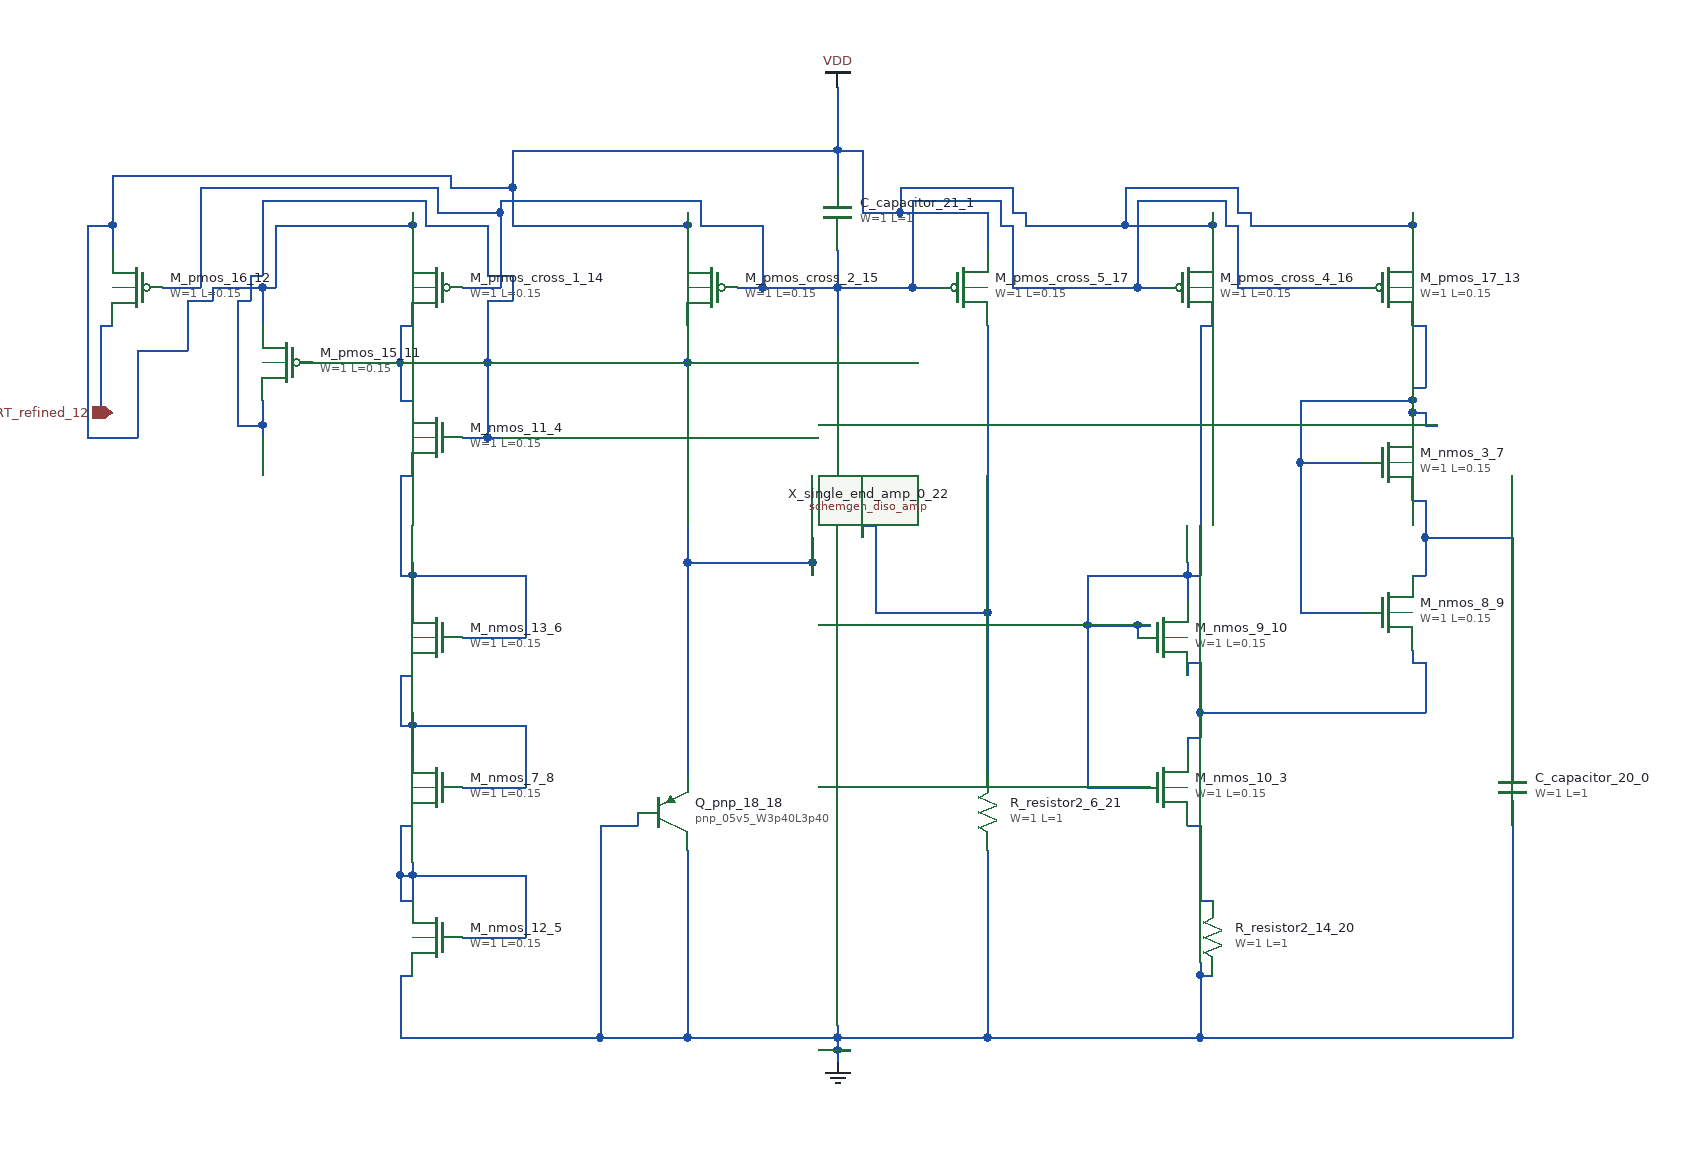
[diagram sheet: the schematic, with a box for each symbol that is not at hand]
v {xschem version=3.4.8 file_version=1.2}
G {}
K {}
V {}
S {}
E {}
C {sky130_fd_pr/cap_mim_m3_1.sym} 1180 600 0 0 {name="C_capacitor_20_0" model=cap_mim_m3_1 W=1 L=1 MF=1 spiceprefix=X}
C {sky130_fd_pr/cap_mim_m3_1.sym} 640 140 2 0 {name="C_capacitor_21_1" model=cap_mim_m3_1 W=1 L=1 MF=1 spiceprefix=X}
C {devices/gnd.sym} 640 820 0 0 {name="l_gnd_19_2" lab="GND"}
C {sky130_fd_pr/nfet3_01v8.sym} 900 600 2 1 {name="M_nmos_10_3"
W=1
L=0.15
body=GND
nf=1
mult=1
ad="expr('int((@nf + 1)/2) * @W / @nf * 0.29')"
pd="expr('2*int((@nf + 1)/2) * (@W / @nf + 0.29)')"
as="expr('int((@nf + 2)/2) * @W / @nf * 0.29')"
ps="expr('2*int((@nf + 2)/2) * (@W / @nf + 0.29)')"
nrd="expr('0.29 / @W ')" nrs="expr('0.29 / @W ')"
sa=0 sb=0 sd=0
model=nfet_01v8
spiceprefix=X
}
C {sky130_fd_pr/nfet3_01v8.sym} 320 320 0 1 {name="M_nmos_11_4"
W=1
L=0.15
body=GND
nf=1
mult=1
ad="expr('int((@nf + 1)/2) * @W / @nf * 0.29')"
pd="expr('2*int((@nf + 1)/2) * (@W / @nf + 0.29)')"
as="expr('int((@nf + 2)/2) * @W / @nf * 0.29')"
ps="expr('2*int((@nf + 2)/2) * (@W / @nf + 0.29)')"
nrd="expr('0.29 / @W ')" nrs="expr('0.29 / @W ')"
sa=0 sb=0 sd=0
model=nfet_01v8
spiceprefix=X
}
C {sky130_fd_pr/nfet3_01v8.sym} 320 720 0 1 {name="M_nmos_12_5"
W=1
L=0.15
body=GND
nf=1
mult=1
ad="expr('int((@nf + 1)/2) * @W / @nf * 0.29')"
pd="expr('2*int((@nf + 1)/2) * (@W / @nf + 0.29)')"
as="expr('int((@nf + 2)/2) * @W / @nf * 0.29')"
ps="expr('2*int((@nf + 2)/2) * (@W / @nf + 0.29)')"
nrd="expr('0.29 / @W ')" nrs="expr('0.29 / @W ')"
sa=0 sb=0 sd=0
model=nfet_01v8
spiceprefix=X
}
C {sky130_fd_pr/nfet3_01v8.sym} 320 480 0 1 {name="M_nmos_13_6"
W=1
L=0.15
body=GND
nf=1
mult=1
ad="expr('int((@nf + 1)/2) * @W / @nf * 0.29')"
pd="expr('2*int((@nf + 1)/2) * (@W / @nf + 0.29)')"
as="expr('int((@nf + 2)/2) * @W / @nf * 0.29')"
ps="expr('2*int((@nf + 2)/2) * (@W / @nf + 0.29)')"
nrd="expr('0.29 / @W ')" nrs="expr('0.29 / @W ')"
sa=0 sb=0 sd=0
model=nfet_01v8
spiceprefix=X
}
C {sky130_fd_pr/nfet3_01v8.sym} 1080 340 0 0 {name="M_nmos_3_7"
W=1
L=0.15
body=GND
nf=1
mult=1
ad="expr('int((@nf + 1)/2) * @W / @nf * 0.29')"
pd="expr('2*int((@nf + 1)/2) * (@W / @nf + 0.29)')"
as="expr('int((@nf + 2)/2) * @W / @nf * 0.29')"
ps="expr('2*int((@nf + 2)/2) * (@W / @nf + 0.29)')"
nrd="expr('0.29 / @W ')" nrs="expr('0.29 / @W ')"
sa=0 sb=0 sd=0
model=nfet_01v8
spiceprefix=X
}
C {sky130_fd_pr/nfet3_01v8.sym} 320 600 0 1 {name="M_nmos_7_8"
W=1
L=0.15
body=GND
nf=1
mult=1
ad="expr('int((@nf + 1)/2) * @W / @nf * 0.29')"
pd="expr('2*int((@nf + 1)/2) * (@W / @nf + 0.29)')"
as="expr('int((@nf + 2)/2) * @W / @nf * 0.29')"
ps="expr('2*int((@nf + 2)/2) * (@W / @nf + 0.29)')"
nrd="expr('0.29 / @W ')" nrs="expr('0.29 / @W ')"
sa=0 sb=0 sd=0
model=nfet_01v8
spiceprefix=X
}
C {sky130_fd_pr/nfet3_01v8.sym} 1080 460 2 1 {name="M_nmos_8_9"
W=1
L=0.15
body=GND
nf=1
mult=1
ad="expr('int((@nf + 1)/2) * @W / @nf * 0.29')"
pd="expr('2*int((@nf + 1)/2) * (@W / @nf + 0.29)')"
as="expr('int((@nf + 2)/2) * @W / @nf * 0.29')"
ps="expr('2*int((@nf + 2)/2) * (@W / @nf + 0.29)')"
nrd="expr('0.29 / @W ')" nrs="expr('0.29 / @W ')"
sa=0 sb=0 sd=0
model=nfet_01v8
spiceprefix=X
}
C {sky130_fd_pr/nfet3_01v8.sym} 900 480 0 0 {name="M_nmos_9_10"
W=1
L=0.15
body=GND
nf=1
mult=1
ad="expr('int((@nf + 1)/2) * @W / @nf * 0.29')"
pd="expr('2*int((@nf + 1)/2) * (@W / @nf + 0.29)')"
as="expr('int((@nf + 2)/2) * @W / @nf * 0.29')"
ps="expr('2*int((@nf + 2)/2) * (@W / @nf + 0.29)')"
nrd="expr('0.29 / @W ')" nrs="expr('0.29 / @W ')"
sa=0 sb=0 sd=0
model=nfet_01v8
spiceprefix=X
}
C {sky130_fd_pr/pfet3_01v8.sym} 200 260 0 1 {name="M_pmos_15_11"
W=1
L=0.15
body=VDD
nf=1
mult=1
ad="expr('int((@nf + 1)/2) * @W / @nf * 0.29')"
pd="expr('2*int((@nf + 1)/2) * (@W / @nf + 0.29)')"
as="expr('int((@nf + 2)/2) * @W / @nf * 0.29')"
ps="expr('2*int((@nf + 2)/2) * (@W / @nf + 0.29)')"
nrd="expr('0.29 / @W ')" nrs="expr('0.29 / @W ')"
sa=0 sb=0 sd=0
model=pfet_01v8
spiceprefix=X
}
C {sky130_fd_pr/pfet3_01v8.sym} 80 200 0 1 {name="M_pmos_16_12"
W=1
L=0.15
body=VDD
nf=1
mult=1
ad="expr('int((@nf + 1)/2) * @W / @nf * 0.29')"
pd="expr('2*int((@nf + 1)/2) * (@W / @nf + 0.29)')"
as="expr('int((@nf + 2)/2) * @W / @nf * 0.29')"
ps="expr('2*int((@nf + 2)/2) * (@W / @nf + 0.29)')"
nrd="expr('0.29 / @W ')" nrs="expr('0.29 / @W ')"
sa=0 sb=0 sd=0
model=pfet_01v8
spiceprefix=X
}
C {sky130_fd_pr/pfet3_01v8.sym} 1080 200 0 0 {name="M_pmos_17_13"
W=1
L=0.15
body=VDD
nf=1
mult=1
ad="expr('int((@nf + 1)/2) * @W / @nf * 0.29')"
pd="expr('2*int((@nf + 1)/2) * (@W / @nf + 0.29)')"
as="expr('int((@nf + 2)/2) * @W / @nf * 0.29')"
ps="expr('2*int((@nf + 2)/2) * (@W / @nf + 0.29)')"
nrd="expr('0.29 / @W ')" nrs="expr('0.29 / @W ')"
sa=0 sb=0 sd=0
model=pfet_01v8
spiceprefix=X
}
C {sky130_fd_pr/pfet3_01v8.sym} 320 200 0 1 {name="M_pmos_cross_1_14"
W=1
L=0.15
body=VDD
nf=1
mult=1
ad="expr('int((@nf + 1)/2) * @W / @nf * 0.29')"
pd="expr('2*int((@nf + 1)/2) * (@W / @nf + 0.29)')"
as="expr('int((@nf + 2)/2) * @W / @nf * 0.29')"
ps="expr('2*int((@nf + 2)/2) * (@W / @nf + 0.29)')"
nrd="expr('0.29 / @W ')" nrs="expr('0.29 / @W ')"
sa=0 sb=0 sd=0
model=pfet_01v8
spiceprefix=X
}
C {sky130_fd_pr/pfet3_01v8.sym} 540 200 0 1 {name="M_pmos_cross_2_15"
W=1
L=0.15
body=VDD
nf=1
mult=1
ad="expr('int((@nf + 1)/2) * @W / @nf * 0.29')"
pd="expr('2*int((@nf + 1)/2) * (@W / @nf + 0.29)')"
as="expr('int((@nf + 2)/2) * @W / @nf * 0.29')"
ps="expr('2*int((@nf + 2)/2) * (@W / @nf + 0.29)')"
nrd="expr('0.29 / @W ')" nrs="expr('0.29 / @W ')"
sa=0 sb=0 sd=0
model=pfet_01v8
spiceprefix=X
}
C {sky130_fd_pr/pfet3_01v8.sym} 920 200 0 0 {name="M_pmos_cross_4_16"
W=1
L=0.15
body=VDD
nf=1
mult=1
ad="expr('int((@nf + 1)/2) * @W / @nf * 0.29')"
pd="expr('2*int((@nf + 1)/2) * (@W / @nf + 0.29)')"
as="expr('int((@nf + 2)/2) * @W / @nf * 0.29')"
ps="expr('2*int((@nf + 2)/2) * (@W / @nf + 0.29)')"
nrd="expr('0.29 / @W ')" nrs="expr('0.29 / @W ')"
sa=0 sb=0 sd=0
model=pfet_01v8
spiceprefix=X
}
C {sky130_fd_pr/pfet3_01v8.sym} 740 200 0 0 {name="M_pmos_cross_5_17"
W=1
L=0.15
body=VDD
nf=1
mult=1
ad="expr('int((@nf + 1)/2) * @W / @nf * 0.29')"
pd="expr('2*int((@nf + 1)/2) * (@W / @nf + 0.29)')"
as="expr('int((@nf + 2)/2) * @W / @nf * 0.29')"
ps="expr('2*int((@nf + 2)/2) * (@W / @nf + 0.29)')"
nrd="expr('0.29 / @W ')" nrs="expr('0.29 / @W ')"
sa=0 sb=0 sd=0
model=pfet_01v8
spiceprefix=X
}
C {sky130_fd_pr/pnp_05v5.sym} 500 620 0 0 {name="Q_pnp_18_18"
model=pnp_05v5_W3p40L3p40
m=1
spiceprefix=X
}
C {devices/ipin.sym} 60 300 0 0 {name="p_port_27_19" lab="PORT_refined_12"}
C {sky130_fd_pr/res_generic_po.sym} 940 720 2 0 {name="R_resistor2_14_20"
W=1
L=1
model=res_generic_po
spiceprefix=X
mult=1}
C {sky130_fd_pr/res_generic_po.sym} 760 620 2 0 {name="R_resistor2_6_21"
W=1
L=1
model=res_generic_po
spiceprefix=X
mult=1}
C {schemgen_diso_amp.sym} 640 320 1 1 {name="X_single_end_amp_0_22"}
C {devices/vdd.sym} 640 40 0 0 {name="l_vdd_22_23" lab="VDD"}
N 640 810 650 810 {}
N 290 800 450 800 {}
N 450 800 520 800 {}
N 520 800 640 800 {}
N 640 800 760 800 {}
N 760 800 930 800 {}
N 930 800 1180 800 {}
N 290 750 300 750 {}
N 930 750 940 750 {}
N 450 630 480 630 {}
N 290 800 290 750 {}
N 450 800 450 630 {}
N 480 630 480 620 {}
N 520 800 520 650 {}
N 640 820 640 810 {}
N 640 810 640 800 {}
N 640 800 640 790 {}
N 760 800 760 650 {}
N 930 800 930 750 {}
N 930 750 930 740 {}
N 1180 800 1180 630 {}
N 1180 630 1180 610 {}
N 1100 430 1110 430 {}
N 1110 400 1180 400 {}
N 1100 370 1110 370 {}
N 1110 430 1110 400 {}
N 1110 400 1110 370 {}
N 1180 590 1180 570 {}
N 1180 570 1180 400 {}
N 520 420 620 420 {}
N 340 320 360 320 {}
N 360 320 370 320 {}
N 160 310 180 310 {}
N 360 260 520 260 {}
N 160 210 170 210 {}
N 360 210 380 210 {}
N 170 190 180 190 {}
N 360 190 380 190 {}
N 310 150 360 150 {}
N 180 130 310 130 {}
N 160 310 160 210 {}
N 170 210 170 190 {}
N 180 320 180 310 {}
N 180 310 180 290 {}
N 180 190 180 130 {}
N 310 150 310 130 {}
N 360 320 360 260 {}
N 360 260 360 210 {}
N 360 190 360 150 {}
N 380 210 380 190 {}
N 520 590 520 420 {}
N 520 420 520 260 {}
N 520 260 520 230 {}
N 620 430 620 420 {}
N 620 420 620 400 {}
N 290 290 300 290 {}
N 210 260 220 260 {}
N 220 260 290 260 {}
N 290 230 300 230 {}
N 290 290 290 260 {}
N 290 260 290 230 {}
N 50 300 60 300 {}
N 50 230 60 230 {}
N 50 300 50 230 {}
N 670 460 760 460 {}
N 660 390 670 390 {}
N 660 400 660 390 {}
N 670 460 670 390 {}
N 760 600 760 590 {}
N 760 590 760 460 {}
N 760 460 760 230 {}
N 930 690 940 690 {}
N 920 630 930 630 {}
N 930 690 930 630 {}
N 100 200 130 200 {}
N 340 200 370 200 {}
N 560 200 580 200 {}
N 580 200 640 200 {}
N 640 200 700 200 {}
N 700 200 720 200 {}
N 780 200 880 200 {}
N 880 200 900 200 {}
N 960 200 1060 200 {}
N 530 150 580 150 {}
N 770 150 780 150 {}
N 950 150 960 150 {}
N 320 140 370 140 {}
N 370 130 530 130 {}
N 700 130 770 130 {}
N 880 130 950 130 {}
N 130 120 320 120 {}
N 130 200 130 120 {}
N 320 140 320 120 {}
N 370 200 370 140 {}
N 370 140 370 130 {}
N 530 150 530 130 {}
N 580 200 580 150 {}
N 640 240 640 200 {}
N 640 200 640 170 {}
N 700 200 700 130 {}
N 770 150 770 130 {}
N 780 200 780 150 {}
N 880 200 880 130 {}
N 950 150 950 130 {}
N 960 200 960 150 {}
N 340 720 390 720 {}
N 290 690 300 690 {}
N 290 670 300 670 {}
N 300 670 390 670 {}
N 290 630 300 630 {}
N 290 690 290 670 {}
N 290 670 290 630 {}
N 300 690 300 670 {}
N 300 670 300 660 {}
N 390 720 390 670 {}
N 340 600 390 600 {}
N 290 550 300 550 {}
N 300 550 390 550 {}
N 290 510 300 510 {}
N 290 550 290 510 {}
N 300 570 300 550 {}
N 300 550 300 540 {}
N 390 600 390 550 {}
N 340 480 390 480 {}
N 290 430 300 430 {}
N 300 430 390 430 {}
N 290 350 300 350 {}
N 290 430 290 350 {}
N 300 450 300 430 {}
N 300 430 300 420 {}
N 390 480 390 430 {}
N 1010 460 1060 460 {}
N 1010 340 1060 340 {}
N 1110 310 1120 310 {}
N 1100 300 1110 300 {}
N 1010 290 1100 290 {}
N 1100 280 1110 280 {}
N 1100 230 1110 230 {}
N 1010 460 1010 340 {}
N 1010 340 1010 290 {}
N 1100 310 1100 300 {}
N 1100 300 1100 290 {}
N 1100 290 1100 280 {}
N 1110 310 1110 300 {}
N 1110 280 1110 230 {}
N 40 320 80 320 {}
N 80 250 120 250 {}
N 120 210 140 210 {}
N 140 200 180 200 {}
N 180 200 190 200 {}
N 40 150 60 150 {}
N 190 150 300 150 {}
N 380 150 520 150 {}
N 790 150 870 150 {}
N 870 150 940 150 {}
N 970 150 1100 150 {}
N 660 140 690 140 {}
N 690 140 760 140 {}
N 780 140 790 140 {}
N 960 140 970 140 {}
N 330 120 380 120 {}
N 690 120 780 120 {}
N 870 120 960 120 {}
N 60 110 330 110 {}
N 380 90 640 90 {}
N 640 90 660 90 {}
N 40 320 40 150 {}
N 60 170 60 150 {}
N 60 150 60 110 {}
N 80 320 80 250 {}
N 120 250 120 210 {}
N 140 210 140 200 {}
N 180 230 180 200 {}
N 190 200 190 150 {}
N 300 170 300 150 {}
N 300 150 300 140 {}
N 330 120 330 110 {}
N 380 150 380 120 {}
N 380 120 380 90 {}
N 520 170 520 150 {}
N 520 150 520 140 {}
N 640 110 640 90 {}
N 640 90 640 40 {}
N 660 140 660 90 {}
N 690 140 690 120 {}
N 760 170 760 140 {}
N 780 140 780 120 {}
N 790 150 790 140 {}
N 870 150 870 120 {}
N 940 170 940 150 {}
N 940 150 940 140 {}
N 960 140 960 120 {}
N 970 150 970 140 {}
N 1100 170 1100 150 {}
N 1100 150 1100 140 {}
N 920 560 930 560 {}
N 930 540 1110 540 {}
N 920 500 930 500 {}
N 1100 500 1110 500 {}
N 920 570 920 560 {}
N 920 510 920 500 {}
N 930 560 930 540 {}
N 930 540 930 500 {}
N 1100 500 1100 490 {}
N 1110 540 1110 500 {}
N 840 600 880 600 {}
N 880 600 890 600 {}
N 840 470 880 470 {}
N 880 470 890 470 {}
N 840 430 920 430 {}
N 920 430 930 430 {}
N 930 230 940 230 {}
N 840 600 840 470 {}
N 840 470 840 430 {}
N 880 480 880 470 {}
N 920 450 920 430 {}
N 920 430 920 420 {}
N 930 430 930 230 {}
